# Abstract 64x96 single-port SRAM (pin interface of OpenROAD-flow-scripts' bsg_fakeram).
# Geometry is an assumption for a 16A-class node, not PDK data.
VERSION 5.8 ;
BUSBITCHARS "[]" ;
DIVIDERCHAR "/" ;

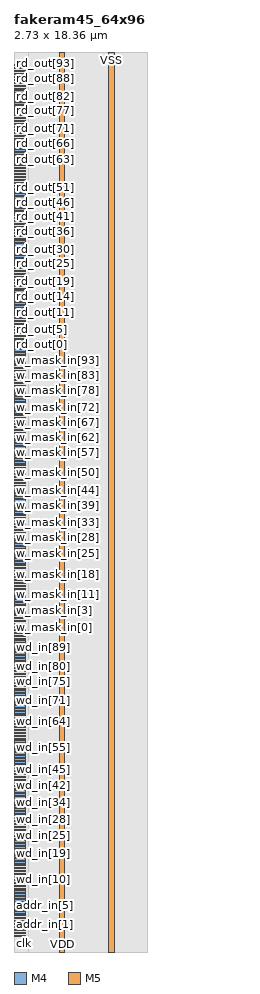
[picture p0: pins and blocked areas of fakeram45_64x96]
MACRO fakeram45_64x96
  CLASS BLOCK ;
  FOREIGN fakeram45_64x96 0 0 ;
  ORIGIN 0 0 ;
  SIZE 2.7300 BY 18.3600 ;
  SYMMETRY X Y R90 ;
  PIN clk
    DIRECTION INPUT ;
    USE CLOCK ;
    PORT
      LAYER M4 ;
        RECT 0 0.3150 0.2400 0.3450 ;
    END
  END clk
  PIN ce_in
    DIRECTION INPUT ;
    USE SIGNAL ;
    PORT
      LAYER M4 ;
        RECT 0 0.3750 0.2400 0.4050 ;
    END
  END ce_in
  PIN we_in
    DIRECTION INPUT ;
    USE SIGNAL ;
    PORT
      LAYER M4 ;
        RECT 0 0.4350 0.2400 0.4650 ;
    END
  END we_in
  PIN addr_in[0]
    DIRECTION INPUT ;
    USE SIGNAL ;
    PORT
      LAYER M4 ;
        RECT 0 0.4950 0.2400 0.5250 ;
    END
  END addr_in[0]
  PIN addr_in[1]
    DIRECTION INPUT ;
    USE SIGNAL ;
    PORT
      LAYER M4 ;
        RECT 0 0.5550 0.2400 0.5850 ;
    END
  END addr_in[1]
  PIN addr_in[2]
    DIRECTION INPUT ;
    USE SIGNAL ;
    PORT
      LAYER M4 ;
        RECT 0 0.6150 0.2400 0.6450 ;
    END
  END addr_in[2]
  PIN addr_in[3]
    DIRECTION INPUT ;
    USE SIGNAL ;
    PORT
      LAYER M4 ;
        RECT 0 0.6750 0.2400 0.7050 ;
    END
  END addr_in[3]
  PIN addr_in[4]
    DIRECTION INPUT ;
    USE SIGNAL ;
    PORT
      LAYER M4 ;
        RECT 0 0.7350 0.2400 0.7650 ;
    END
  END addr_in[4]
  PIN addr_in[5]
    DIRECTION INPUT ;
    USE SIGNAL ;
    PORT
      LAYER M4 ;
        RECT 0 0.7950 0.2400 0.8250 ;
    END
  END addr_in[5]
  PIN wd_in[0]
    DIRECTION INPUT ;
    USE SIGNAL ;
    PORT
      LAYER M4 ;
        RECT 0 0.8550 0.2400 0.8850 ;
    END
  END wd_in[0]
  PIN wd_in[1]
    DIRECTION INPUT ;
    USE SIGNAL ;
    PORT
      LAYER M4 ;
        RECT 0 0.9150 0.2400 0.9450 ;
    END
  END wd_in[1]
  PIN wd_in[2]
    DIRECTION INPUT ;
    USE SIGNAL ;
    PORT
      LAYER M4 ;
        RECT 0 0.9750 0.2400 1.0050 ;
    END
  END wd_in[2]
  PIN wd_in[3]
    DIRECTION INPUT ;
    USE SIGNAL ;
    PORT
      LAYER M4 ;
        RECT 0 1.0350 0.2400 1.0650 ;
    END
  END wd_in[3]
  PIN wd_in[4]
    DIRECTION INPUT ;
    USE SIGNAL ;
    PORT
      LAYER M4 ;
        RECT 0 1.0950 0.2400 1.1250 ;
    END
  END wd_in[4]
  PIN wd_in[5]
    DIRECTION INPUT ;
    USE SIGNAL ;
    PORT
      LAYER M4 ;
        RECT 0 1.1550 0.2400 1.1850 ;
    END
  END wd_in[5]
  PIN wd_in[6]
    DIRECTION INPUT ;
    USE SIGNAL ;
    PORT
      LAYER M4 ;
        RECT 0 1.2150 0.2400 1.2450 ;
    END
  END wd_in[6]
  PIN wd_in[7]
    DIRECTION INPUT ;
    USE SIGNAL ;
    PORT
      LAYER M4 ;
        RECT 0 1.2750 0.2400 1.3050 ;
    END
  END wd_in[7]
  PIN wd_in[8]
    DIRECTION INPUT ;
    USE SIGNAL ;
    PORT
      LAYER M4 ;
        RECT 0 1.3350 0.2400 1.3650 ;
    END
  END wd_in[8]
  PIN wd_in[9]
    DIRECTION INPUT ;
    USE SIGNAL ;
    PORT
      LAYER M4 ;
        RECT 0 1.3950 0.2400 1.4250 ;
    END
  END wd_in[9]
  PIN wd_in[10]
    DIRECTION INPUT ;
    USE SIGNAL ;
    PORT
      LAYER M4 ;
        RECT 0 1.4550 0.2400 1.4850 ;
    END
  END wd_in[10]
  PIN wd_in[11]
    DIRECTION INPUT ;
    USE SIGNAL ;
    PORT
      LAYER M4 ;
        RECT 0 1.5150 0.2400 1.5450 ;
    END
  END wd_in[11]
  PIN wd_in[12]
    DIRECTION INPUT ;
    USE SIGNAL ;
    PORT
      LAYER M4 ;
        RECT 0 1.5750 0.2400 1.6050 ;
    END
  END wd_in[12]
  PIN wd_in[13]
    DIRECTION INPUT ;
    USE SIGNAL ;
    PORT
      LAYER M4 ;
        RECT 0 1.6350 0.2400 1.6650 ;
    END
  END wd_in[13]
  PIN wd_in[14]
    DIRECTION INPUT ;
    USE SIGNAL ;
    PORT
      LAYER M4 ;
        RECT 0 1.6950 0.2400 1.7250 ;
    END
  END wd_in[14]
  PIN wd_in[15]
    DIRECTION INPUT ;
    USE SIGNAL ;
    PORT
      LAYER M4 ;
        RECT 0 1.7550 0.2400 1.7850 ;
    END
  END wd_in[15]
  PIN wd_in[16]
    DIRECTION INPUT ;
    USE SIGNAL ;
    PORT
      LAYER M4 ;
        RECT 0 1.8150 0.2400 1.8450 ;
    END
  END wd_in[16]
  PIN wd_in[17]
    DIRECTION INPUT ;
    USE SIGNAL ;
    PORT
      LAYER M4 ;
        RECT 0 1.8750 0.2400 1.9050 ;
    END
  END wd_in[17]
  PIN wd_in[18]
    DIRECTION INPUT ;
    USE SIGNAL ;
    PORT
      LAYER M4 ;
        RECT 0 1.9350 0.2400 1.9650 ;
    END
  END wd_in[18]
  PIN wd_in[19]
    DIRECTION INPUT ;
    USE SIGNAL ;
    PORT
      LAYER M4 ;
        RECT 0 1.9950 0.2400 2.0250 ;
    END
  END wd_in[19]
  PIN wd_in[20]
    DIRECTION INPUT ;
    USE SIGNAL ;
    PORT
      LAYER M4 ;
        RECT 0 2.0550 0.2400 2.0850 ;
    END
  END wd_in[20]
  PIN wd_in[21]
    DIRECTION INPUT ;
    USE SIGNAL ;
    PORT
      LAYER M4 ;
        RECT 0 2.1150 0.2400 2.1450 ;
    END
  END wd_in[21]
  PIN wd_in[22]
    DIRECTION INPUT ;
    USE SIGNAL ;
    PORT
      LAYER M4 ;
        RECT 0 2.1750 0.2400 2.2050 ;
    END
  END wd_in[22]
  PIN wd_in[23]
    DIRECTION INPUT ;
    USE SIGNAL ;
    PORT
      LAYER M4 ;
        RECT 0 2.2350 0.2400 2.2650 ;
    END
  END wd_in[23]
  PIN wd_in[24]
    DIRECTION INPUT ;
    USE SIGNAL ;
    PORT
      LAYER M4 ;
        RECT 0 2.2950 0.2400 2.3250 ;
    END
  END wd_in[24]
  PIN wd_in[25]
    DIRECTION INPUT ;
    USE SIGNAL ;
    PORT
      LAYER M4 ;
        RECT 0 2.3550 0.2400 2.3850 ;
    END
  END wd_in[25]
  PIN wd_in[26]
    DIRECTION INPUT ;
    USE SIGNAL ;
    PORT
      LAYER M4 ;
        RECT 0 2.4150 0.2400 2.4450 ;
    END
  END wd_in[26]
  PIN wd_in[27]
    DIRECTION INPUT ;
    USE SIGNAL ;
    PORT
      LAYER M4 ;
        RECT 0 2.4750 0.2400 2.5050 ;
    END
  END wd_in[27]
  PIN wd_in[28]
    DIRECTION INPUT ;
    USE SIGNAL ;
    PORT
      LAYER M4 ;
        RECT 0 2.5350 0.2400 2.5650 ;
    END
  END wd_in[28]
  PIN wd_in[29]
    DIRECTION INPUT ;
    USE SIGNAL ;
    PORT
      LAYER M4 ;
        RECT 0 2.5950 0.2400 2.6250 ;
    END
  END wd_in[29]
  PIN wd_in[30]
    DIRECTION INPUT ;
    USE SIGNAL ;
    PORT
      LAYER M4 ;
        RECT 0 2.6550 0.2400 2.6850 ;
    END
  END wd_in[30]
  PIN wd_in[31]
    DIRECTION INPUT ;
    USE SIGNAL ;
    PORT
      LAYER M4 ;
        RECT 0 2.7150 0.2400 2.7450 ;
    END
  END wd_in[31]
  PIN wd_in[32]
    DIRECTION INPUT ;
    USE SIGNAL ;
    PORT
      LAYER M4 ;
        RECT 0 2.7750 0.2400 2.8050 ;
    END
  END wd_in[32]
  PIN wd_in[33]
    DIRECTION INPUT ;
    USE SIGNAL ;
    PORT
      LAYER M4 ;
        RECT 0 2.8350 0.2400 2.8650 ;
    END
  END wd_in[33]
  PIN wd_in[34]
    DIRECTION INPUT ;
    USE SIGNAL ;
    PORT
      LAYER M4 ;
        RECT 0 2.8950 0.2400 2.9250 ;
    END
  END wd_in[34]
  PIN wd_in[35]
    DIRECTION INPUT ;
    USE SIGNAL ;
    PORT
      LAYER M4 ;
        RECT 0 2.9550 0.2400 2.9850 ;
    END
  END wd_in[35]
  PIN wd_in[36]
    DIRECTION INPUT ;
    USE SIGNAL ;
    PORT
      LAYER M4 ;
        RECT 0 3.0150 0.2400 3.0450 ;
    END
  END wd_in[36]
  PIN wd_in[37]
    DIRECTION INPUT ;
    USE SIGNAL ;
    PORT
      LAYER M4 ;
        RECT 0 3.0750 0.2400 3.1050 ;
    END
  END wd_in[37]
  PIN wd_in[38]
    DIRECTION INPUT ;
    USE SIGNAL ;
    PORT
      LAYER M4 ;
        RECT 0 3.1350 0.2400 3.1650 ;
    END
  END wd_in[38]
  PIN wd_in[39]
    DIRECTION INPUT ;
    USE SIGNAL ;
    PORT
      LAYER M4 ;
        RECT 0 3.1950 0.2400 3.2250 ;
    END
  END wd_in[39]
  PIN wd_in[40]
    DIRECTION INPUT ;
    USE SIGNAL ;
    PORT
      LAYER M4 ;
        RECT 0 3.2550 0.2400 3.2850 ;
    END
  END wd_in[40]
  PIN wd_in[41]
    DIRECTION INPUT ;
    USE SIGNAL ;
    PORT
      LAYER M4 ;
        RECT 0 3.3150 0.2400 3.3450 ;
    END
  END wd_in[41]
  PIN wd_in[42]
    DIRECTION INPUT ;
    USE SIGNAL ;
    PORT
      LAYER M4 ;
        RECT 0 3.3750 0.2400 3.4050 ;
    END
  END wd_in[42]
  PIN wd_in[43]
    DIRECTION INPUT ;
    USE SIGNAL ;
    PORT
      LAYER M4 ;
        RECT 0 3.4350 0.2400 3.4650 ;
    END
  END wd_in[43]
  PIN wd_in[44]
    DIRECTION INPUT ;
    USE SIGNAL ;
    PORT
      LAYER M4 ;
        RECT 0 3.4950 0.2400 3.5250 ;
    END
  END wd_in[44]
  PIN wd_in[45]
    DIRECTION INPUT ;
    USE SIGNAL ;
    PORT
      LAYER M4 ;
        RECT 0 3.5550 0.2400 3.5850 ;
    END
  END wd_in[45]
  PIN wd_in[46]
    DIRECTION INPUT ;
    USE SIGNAL ;
    PORT
      LAYER M4 ;
        RECT 0 3.6150 0.2400 3.6450 ;
    END
  END wd_in[46]
  PIN wd_in[47]
    DIRECTION INPUT ;
    USE SIGNAL ;
    PORT
      LAYER M4 ;
        RECT 0 3.6750 0.2400 3.7050 ;
    END
  END wd_in[47]
  PIN wd_in[48]
    DIRECTION INPUT ;
    USE SIGNAL ;
    PORT
      LAYER M4 ;
        RECT 0 3.7350 0.2400 3.7650 ;
    END
  END wd_in[48]
  PIN wd_in[49]
    DIRECTION INPUT ;
    USE SIGNAL ;
    PORT
      LAYER M4 ;
        RECT 0 3.7950 0.2400 3.8250 ;
    END
  END wd_in[49]
  PIN wd_in[50]
    DIRECTION INPUT ;
    USE SIGNAL ;
    PORT
      LAYER M4 ;
        RECT 0 3.8550 0.2400 3.8850 ;
    END
  END wd_in[50]
  PIN wd_in[51]
    DIRECTION INPUT ;
    USE SIGNAL ;
    PORT
      LAYER M4 ;
        RECT 0 3.9150 0.2400 3.9450 ;
    END
  END wd_in[51]
  PIN wd_in[52]
    DIRECTION INPUT ;
    USE SIGNAL ;
    PORT
      LAYER M4 ;
        RECT 0 3.9750 0.2400 4.0050 ;
    END
  END wd_in[52]
  PIN wd_in[53]
    DIRECTION INPUT ;
    USE SIGNAL ;
    PORT
      LAYER M4 ;
        RECT 0 4.0350 0.2400 4.0650 ;
    END
  END wd_in[53]
  PIN wd_in[54]
    DIRECTION INPUT ;
    USE SIGNAL ;
    PORT
      LAYER M4 ;
        RECT 0 4.0950 0.2400 4.1250 ;
    END
  END wd_in[54]
  PIN wd_in[55]
    DIRECTION INPUT ;
    USE SIGNAL ;
    PORT
      LAYER M4 ;
        RECT 0 4.1550 0.2400 4.1850 ;
    END
  END wd_in[55]
  PIN wd_in[56]
    DIRECTION INPUT ;
    USE SIGNAL ;
    PORT
      LAYER M4 ;
        RECT 0 4.2150 0.2400 4.2450 ;
    END
  END wd_in[56]
  PIN wd_in[57]
    DIRECTION INPUT ;
    USE SIGNAL ;
    PORT
      LAYER M4 ;
        RECT 0 4.2750 0.2400 4.3050 ;
    END
  END wd_in[57]
  PIN wd_in[58]
    DIRECTION INPUT ;
    USE SIGNAL ;
    PORT
      LAYER M4 ;
        RECT 0 4.3350 0.2400 4.3650 ;
    END
  END wd_in[58]
  PIN wd_in[59]
    DIRECTION INPUT ;
    USE SIGNAL ;
    PORT
      LAYER M4 ;
        RECT 0 4.3950 0.2400 4.4250 ;
    END
  END wd_in[59]
  PIN wd_in[60]
    DIRECTION INPUT ;
    USE SIGNAL ;
    PORT
      LAYER M4 ;
        RECT 0 4.4550 0.2400 4.4850 ;
    END
  END wd_in[60]
  PIN wd_in[61]
    DIRECTION INPUT ;
    USE SIGNAL ;
    PORT
      LAYER M4 ;
        RECT 0 4.5150 0.2400 4.5450 ;
    END
  END wd_in[61]
  PIN wd_in[62]
    DIRECTION INPUT ;
    USE SIGNAL ;
    PORT
      LAYER M4 ;
        RECT 0 4.5750 0.2400 4.6050 ;
    END
  END wd_in[62]
  PIN wd_in[63]
    DIRECTION INPUT ;
    USE SIGNAL ;
    PORT
      LAYER M4 ;
        RECT 0 4.6350 0.2400 4.6650 ;
    END
  END wd_in[63]
  PIN wd_in[64]
    DIRECTION INPUT ;
    USE SIGNAL ;
    PORT
      LAYER M4 ;
        RECT 0 4.6950 0.2400 4.7250 ;
    END
  END wd_in[64]
  PIN wd_in[65]
    DIRECTION INPUT ;
    USE SIGNAL ;
    PORT
      LAYER M4 ;
        RECT 0 4.7550 0.2400 4.7850 ;
    END
  END wd_in[65]
  PIN wd_in[66]
    DIRECTION INPUT ;
    USE SIGNAL ;
    PORT
      LAYER M4 ;
        RECT 0 4.8150 0.2400 4.8450 ;
    END
  END wd_in[66]
  PIN wd_in[67]
    DIRECTION INPUT ;
    USE SIGNAL ;
    PORT
      LAYER M4 ;
        RECT 0 4.8750 0.2400 4.9050 ;
    END
  END wd_in[67]
  PIN wd_in[68]
    DIRECTION INPUT ;
    USE SIGNAL ;
    PORT
      LAYER M4 ;
        RECT 0 4.9350 0.2400 4.9650 ;
    END
  END wd_in[68]
  PIN wd_in[69]
    DIRECTION INPUT ;
    USE SIGNAL ;
    PORT
      LAYER M4 ;
        RECT 0 4.9950 0.2400 5.0250 ;
    END
  END wd_in[69]
  PIN wd_in[70]
    DIRECTION INPUT ;
    USE SIGNAL ;
    PORT
      LAYER M4 ;
        RECT 0 5.0550 0.2400 5.0850 ;
    END
  END wd_in[70]
  PIN wd_in[71]
    DIRECTION INPUT ;
    USE SIGNAL ;
    PORT
      LAYER M4 ;
        RECT 0 5.1150 0.2400 5.1450 ;
    END
  END wd_in[71]
  PIN wd_in[72]
    DIRECTION INPUT ;
    USE SIGNAL ;
    PORT
      LAYER M4 ;
        RECT 0 5.1750 0.2400 5.2050 ;
    END
  END wd_in[72]
  PIN wd_in[73]
    DIRECTION INPUT ;
    USE SIGNAL ;
    PORT
      LAYER M4 ;
        RECT 0 5.2350 0.2400 5.2650 ;
    END
  END wd_in[73]
  PIN wd_in[74]
    DIRECTION INPUT ;
    USE SIGNAL ;
    PORT
      LAYER M4 ;
        RECT 0 5.2950 0.2400 5.3250 ;
    END
  END wd_in[74]
  PIN wd_in[75]
    DIRECTION INPUT ;
    USE SIGNAL ;
    PORT
      LAYER M4 ;
        RECT 0 5.3550 0.2400 5.3850 ;
    END
  END wd_in[75]
  PIN wd_in[76]
    DIRECTION INPUT ;
    USE SIGNAL ;
    PORT
      LAYER M4 ;
        RECT 0 5.4150 0.2400 5.4450 ;
    END
  END wd_in[76]
  PIN wd_in[77]
    DIRECTION INPUT ;
    USE SIGNAL ;
    PORT
      LAYER M4 ;
        RECT 0 5.4750 0.2400 5.5050 ;
    END
  END wd_in[77]
  PIN wd_in[78]
    DIRECTION INPUT ;
    USE SIGNAL ;
    PORT
      LAYER M4 ;
        RECT 0 5.5350 0.2400 5.5650 ;
    END
  END wd_in[78]
  PIN wd_in[79]
    DIRECTION INPUT ;
    USE SIGNAL ;
    PORT
      LAYER M4 ;
        RECT 0 5.5950 0.2400 5.6250 ;
    END
  END wd_in[79]
  PIN wd_in[80]
    DIRECTION INPUT ;
    USE SIGNAL ;
    PORT
      LAYER M4 ;
        RECT 0 5.6550 0.2400 5.6850 ;
    END
  END wd_in[80]
  PIN wd_in[81]
    DIRECTION INPUT ;
    USE SIGNAL ;
    PORT
      LAYER M4 ;
        RECT 0 5.7150 0.2400 5.7450 ;
    END
  END wd_in[81]
  PIN wd_in[82]
    DIRECTION INPUT ;
    USE SIGNAL ;
    PORT
      LAYER M4 ;
        RECT 0 5.7750 0.2400 5.8050 ;
    END
  END wd_in[82]
  PIN wd_in[83]
    DIRECTION INPUT ;
    USE SIGNAL ;
    PORT
      LAYER M4 ;
        RECT 0 5.8350 0.2400 5.8650 ;
    END
  END wd_in[83]
  PIN wd_in[84]
    DIRECTION INPUT ;
    USE SIGNAL ;
    PORT
      LAYER M4 ;
        RECT 0 5.8950 0.2400 5.9250 ;
    END
  END wd_in[84]
  PIN wd_in[85]
    DIRECTION INPUT ;
    USE SIGNAL ;
    PORT
      LAYER M4 ;
        RECT 0 5.9550 0.2400 5.9850 ;
    END
  END wd_in[85]
  PIN wd_in[86]
    DIRECTION INPUT ;
    USE SIGNAL ;
    PORT
      LAYER M4 ;
        RECT 0 6.0150 0.2400 6.0450 ;
    END
  END wd_in[86]
  PIN wd_in[87]
    DIRECTION INPUT ;
    USE SIGNAL ;
    PORT
      LAYER M4 ;
        RECT 0 6.0750 0.2400 6.1050 ;
    END
  END wd_in[87]
  PIN wd_in[88]
    DIRECTION INPUT ;
    USE SIGNAL ;
    PORT
      LAYER M4 ;
        RECT 0 6.1350 0.2400 6.1650 ;
    END
  END wd_in[88]
  PIN wd_in[89]
    DIRECTION INPUT ;
    USE SIGNAL ;
    PORT
      LAYER M4 ;
        RECT 0 6.1950 0.2400 6.2250 ;
    END
  END wd_in[89]
  PIN wd_in[90]
    DIRECTION INPUT ;
    USE SIGNAL ;
    PORT
      LAYER M4 ;
        RECT 0 6.2550 0.2400 6.2850 ;
    END
  END wd_in[90]
  PIN wd_in[91]
    DIRECTION INPUT ;
    USE SIGNAL ;
    PORT
      LAYER M4 ;
        RECT 0 6.3150 0.2400 6.3450 ;
    END
  END wd_in[91]
  PIN wd_in[92]
    DIRECTION INPUT ;
    USE SIGNAL ;
    PORT
      LAYER M4 ;
        RECT 0 6.3750 0.2400 6.4050 ;
    END
  END wd_in[92]
  PIN wd_in[93]
    DIRECTION INPUT ;
    USE SIGNAL ;
    PORT
      LAYER M4 ;
        RECT 0 6.4350 0.2400 6.4650 ;
    END
  END wd_in[93]
  PIN wd_in[94]
    DIRECTION INPUT ;
    USE SIGNAL ;
    PORT
      LAYER M4 ;
        RECT 0 6.4950 0.2400 6.5250 ;
    END
  END wd_in[94]
  PIN wd_in[95]
    DIRECTION INPUT ;
    USE SIGNAL ;
    PORT
      LAYER M4 ;
        RECT 0 6.5550 0.2400 6.5850 ;
    END
  END wd_in[95]
  PIN w_mask_in[0]
    DIRECTION INPUT ;
    USE SIGNAL ;
    PORT
      LAYER M4 ;
        RECT 0 6.6150 0.2400 6.6450 ;
    END
  END w_mask_in[0]
  PIN w_mask_in[1]
    DIRECTION INPUT ;
    USE SIGNAL ;
    PORT
      LAYER M4 ;
        RECT 0 6.6750 0.2400 6.7050 ;
    END
  END w_mask_in[1]
  PIN w_mask_in[2]
    DIRECTION INPUT ;
    USE SIGNAL ;
    PORT
      LAYER M4 ;
        RECT 0 6.7350 0.2400 6.7650 ;
    END
  END w_mask_in[2]
  PIN w_mask_in[3]
    DIRECTION INPUT ;
    USE SIGNAL ;
    PORT
      LAYER M4 ;
        RECT 0 6.7950 0.2400 6.8250 ;
    END
  END w_mask_in[3]
  PIN w_mask_in[4]
    DIRECTION INPUT ;
    USE SIGNAL ;
    PORT
      LAYER M4 ;
        RECT 0 6.8550 0.2400 6.8850 ;
    END
  END w_mask_in[4]
  PIN w_mask_in[5]
    DIRECTION INPUT ;
    USE SIGNAL ;
    PORT
      LAYER M4 ;
        RECT 0 6.9150 0.2400 6.9450 ;
    END
  END w_mask_in[5]
  PIN w_mask_in[6]
    DIRECTION INPUT ;
    USE SIGNAL ;
    PORT
      LAYER M4 ;
        RECT 0 6.9750 0.2400 7.0050 ;
    END
  END w_mask_in[6]
  PIN w_mask_in[7]
    DIRECTION INPUT ;
    USE SIGNAL ;
    PORT
      LAYER M4 ;
        RECT 0 7.0350 0.2400 7.0650 ;
    END
  END w_mask_in[7]
  PIN w_mask_in[8]
    DIRECTION INPUT ;
    USE SIGNAL ;
    PORT
      LAYER M4 ;
        RECT 0 7.0950 0.2400 7.1250 ;
    END
  END w_mask_in[8]
  PIN w_mask_in[9]
    DIRECTION INPUT ;
    USE SIGNAL ;
    PORT
      LAYER M4 ;
        RECT 0 7.1550 0.2400 7.1850 ;
    END
  END w_mask_in[9]
  PIN w_mask_in[10]
    DIRECTION INPUT ;
    USE SIGNAL ;
    PORT
      LAYER M4 ;
        RECT 0 7.2150 0.2400 7.2450 ;
    END
  END w_mask_in[10]
  PIN w_mask_in[11]
    DIRECTION INPUT ;
    USE SIGNAL ;
    PORT
      LAYER M4 ;
        RECT 0 7.2750 0.2400 7.3050 ;
    END
  END w_mask_in[11]
  PIN w_mask_in[12]
    DIRECTION INPUT ;
    USE SIGNAL ;
    PORT
      LAYER M4 ;
        RECT 0 7.3350 0.2400 7.3650 ;
    END
  END w_mask_in[12]
  PIN w_mask_in[13]
    DIRECTION INPUT ;
    USE SIGNAL ;
    PORT
      LAYER M4 ;
        RECT 0 7.3950 0.2400 7.4250 ;
    END
  END w_mask_in[13]
  PIN w_mask_in[14]
    DIRECTION INPUT ;
    USE SIGNAL ;
    PORT
      LAYER M4 ;
        RECT 0 7.4550 0.2400 7.4850 ;
    END
  END w_mask_in[14]
  PIN w_mask_in[15]
    DIRECTION INPUT ;
    USE SIGNAL ;
    PORT
      LAYER M4 ;
        RECT 0 7.5150 0.2400 7.5450 ;
    END
  END w_mask_in[15]
  PIN w_mask_in[16]
    DIRECTION INPUT ;
    USE SIGNAL ;
    PORT
      LAYER M4 ;
        RECT 0 7.5750 0.2400 7.6050 ;
    END
  END w_mask_in[16]
  PIN w_mask_in[17]
    DIRECTION INPUT ;
    USE SIGNAL ;
    PORT
      LAYER M4 ;
        RECT 0 7.6350 0.2400 7.6650 ;
    END
  END w_mask_in[17]
  PIN w_mask_in[18]
    DIRECTION INPUT ;
    USE SIGNAL ;
    PORT
      LAYER M4 ;
        RECT 0 7.6950 0.2400 7.7250 ;
    END
  END w_mask_in[18]
  PIN w_mask_in[19]
    DIRECTION INPUT ;
    USE SIGNAL ;
    PORT
      LAYER M4 ;
        RECT 0 7.7550 0.2400 7.7850 ;
    END
  END w_mask_in[19]
  PIN w_mask_in[20]
    DIRECTION INPUT ;
    USE SIGNAL ;
    PORT
      LAYER M4 ;
        RECT 0 7.8150 0.2400 7.8450 ;
    END
  END w_mask_in[20]
  PIN w_mask_in[21]
    DIRECTION INPUT ;
    USE SIGNAL ;
    PORT
      LAYER M4 ;
        RECT 0 7.8750 0.2400 7.9050 ;
    END
  END w_mask_in[21]
  PIN w_mask_in[22]
    DIRECTION INPUT ;
    USE SIGNAL ;
    PORT
      LAYER M4 ;
        RECT 0 7.9350 0.2400 7.9650 ;
    END
  END w_mask_in[22]
  PIN w_mask_in[23]
    DIRECTION INPUT ;
    USE SIGNAL ;
    PORT
      LAYER M4 ;
        RECT 0 7.9950 0.2400 8.0250 ;
    END
  END w_mask_in[23]
  PIN w_mask_in[24]
    DIRECTION INPUT ;
    USE SIGNAL ;
    PORT
      LAYER M4 ;
        RECT 0 8.0550 0.2400 8.0850 ;
    END
  END w_mask_in[24]
  PIN w_mask_in[25]
    DIRECTION INPUT ;
    USE SIGNAL ;
    PORT
      LAYER M4 ;
        RECT 0 8.1150 0.2400 8.1450 ;
    END
  END w_mask_in[25]
  PIN w_mask_in[26]
    DIRECTION INPUT ;
    USE SIGNAL ;
    PORT
      LAYER M4 ;
        RECT 0 8.1750 0.2400 8.2050 ;
    END
  END w_mask_in[26]
  PIN w_mask_in[27]
    DIRECTION INPUT ;
    USE SIGNAL ;
    PORT
      LAYER M4 ;
        RECT 0 8.2350 0.2400 8.2650 ;
    END
  END w_mask_in[27]
  PIN w_mask_in[28]
    DIRECTION INPUT ;
    USE SIGNAL ;
    PORT
      LAYER M4 ;
        RECT 0 8.2950 0.2400 8.3250 ;
    END
  END w_mask_in[28]
  PIN w_mask_in[29]
    DIRECTION INPUT ;
    USE SIGNAL ;
    PORT
      LAYER M4 ;
        RECT 0 8.3550 0.2400 8.3850 ;
    END
  END w_mask_in[29]
  PIN w_mask_in[30]
    DIRECTION INPUT ;
    USE SIGNAL ;
    PORT
      LAYER M4 ;
        RECT 0 8.4150 0.2400 8.4450 ;
    END
  END w_mask_in[30]
  PIN w_mask_in[31]
    DIRECTION INPUT ;
    USE SIGNAL ;
    PORT
      LAYER M4 ;
        RECT 0 8.4750 0.2400 8.5050 ;
    END
  END w_mask_in[31]
  PIN w_mask_in[32]
    DIRECTION INPUT ;
    USE SIGNAL ;
    PORT
      LAYER M4 ;
        RECT 0 8.5350 0.2400 8.5650 ;
    END
  END w_mask_in[32]
  PIN w_mask_in[33]
    DIRECTION INPUT ;
    USE SIGNAL ;
    PORT
      LAYER M4 ;
        RECT 0 8.5950 0.2400 8.6250 ;
    END
  END w_mask_in[33]
  PIN w_mask_in[34]
    DIRECTION INPUT ;
    USE SIGNAL ;
    PORT
      LAYER M4 ;
        RECT 0 8.6550 0.2400 8.6850 ;
    END
  END w_mask_in[34]
  PIN w_mask_in[35]
    DIRECTION INPUT ;
    USE SIGNAL ;
    PORT
      LAYER M4 ;
        RECT 0 8.7150 0.2400 8.7450 ;
    END
  END w_mask_in[35]
  PIN w_mask_in[36]
    DIRECTION INPUT ;
    USE SIGNAL ;
    PORT
      LAYER M4 ;
        RECT 0 8.7750 0.2400 8.8050 ;
    END
  END w_mask_in[36]
  PIN w_mask_in[37]
    DIRECTION INPUT ;
    USE SIGNAL ;
    PORT
      LAYER M4 ;
        RECT 0 8.8350 0.2400 8.8650 ;
    END
  END w_mask_in[37]
  PIN w_mask_in[38]
    DIRECTION INPUT ;
    USE SIGNAL ;
    PORT
      LAYER M4 ;
        RECT 0 8.8950 0.2400 8.9250 ;
    END
  END w_mask_in[38]
  PIN w_mask_in[39]
    DIRECTION INPUT ;
    USE SIGNAL ;
    PORT
      LAYER M4 ;
        RECT 0 8.9550 0.2400 8.9850 ;
    END
  END w_mask_in[39]
  PIN w_mask_in[40]
    DIRECTION INPUT ;
    USE SIGNAL ;
    PORT
      LAYER M4 ;
        RECT 0 9.0150 0.2400 9.0450 ;
    END
  END w_mask_in[40]
  PIN w_mask_in[41]
    DIRECTION INPUT ;
    USE SIGNAL ;
    PORT
      LAYER M4 ;
        RECT 0 9.0750 0.2400 9.1050 ;
    END
  END w_mask_in[41]
  PIN w_mask_in[42]
    DIRECTION INPUT ;
    USE SIGNAL ;
    PORT
      LAYER M4 ;
        RECT 0 9.1350 0.2400 9.1650 ;
    END
  END w_mask_in[42]
  PIN w_mask_in[43]
    DIRECTION INPUT ;
    USE SIGNAL ;
    PORT
      LAYER M4 ;
        RECT 0 9.1950 0.2400 9.2250 ;
    END
  END w_mask_in[43]
  PIN w_mask_in[44]
    DIRECTION INPUT ;
    USE SIGNAL ;
    PORT
      LAYER M4 ;
        RECT 0 9.2550 0.2400 9.2850 ;
    END
  END w_mask_in[44]
  PIN w_mask_in[45]
    DIRECTION INPUT ;
    USE SIGNAL ;
    PORT
      LAYER M4 ;
        RECT 0 9.3150 0.2400 9.3450 ;
    END
  END w_mask_in[45]
  PIN w_mask_in[46]
    DIRECTION INPUT ;
    USE SIGNAL ;
    PORT
      LAYER M4 ;
        RECT 0 9.3750 0.2400 9.4050 ;
    END
  END w_mask_in[46]
  PIN w_mask_in[47]
    DIRECTION INPUT ;
    USE SIGNAL ;
    PORT
      LAYER M4 ;
        RECT 0 9.4350 0.2400 9.4650 ;
    END
  END w_mask_in[47]
  PIN w_mask_in[48]
    DIRECTION INPUT ;
    USE SIGNAL ;
    PORT
      LAYER M4 ;
        RECT 0 9.4950 0.2400 9.5250 ;
    END
  END w_mask_in[48]
  PIN w_mask_in[49]
    DIRECTION INPUT ;
    USE SIGNAL ;
    PORT
      LAYER M4 ;
        RECT 0 9.5550 0.2400 9.5850 ;
    END
  END w_mask_in[49]
  PIN w_mask_in[50]
    DIRECTION INPUT ;
    USE SIGNAL ;
    PORT
      LAYER M4 ;
        RECT 0 9.6150 0.2400 9.6450 ;
    END
  END w_mask_in[50]
  PIN w_mask_in[51]
    DIRECTION INPUT ;
    USE SIGNAL ;
    PORT
      LAYER M4 ;
        RECT 0 9.6750 0.2400 9.7050 ;
    END
  END w_mask_in[51]
  PIN w_mask_in[52]
    DIRECTION INPUT ;
    USE SIGNAL ;
    PORT
      LAYER M4 ;
        RECT 0 9.7350 0.2400 9.7650 ;
    END
  END w_mask_in[52]
  PIN w_mask_in[53]
    DIRECTION INPUT ;
    USE SIGNAL ;
    PORT
      LAYER M4 ;
        RECT 0 9.7950 0.2400 9.8250 ;
    END
  END w_mask_in[53]
  PIN w_mask_in[54]
    DIRECTION INPUT ;
    USE SIGNAL ;
    PORT
      LAYER M4 ;
        RECT 0 9.8550 0.2400 9.8850 ;
    END
  END w_mask_in[54]
  PIN w_mask_in[55]
    DIRECTION INPUT ;
    USE SIGNAL ;
    PORT
      LAYER M4 ;
        RECT 0 9.9150 0.2400 9.9450 ;
    END
  END w_mask_in[55]
  PIN w_mask_in[56]
    DIRECTION INPUT ;
    USE SIGNAL ;
    PORT
      LAYER M4 ;
        RECT 0 9.9750 0.2400 10.0050 ;
    END
  END w_mask_in[56]
  PIN w_mask_in[57]
    DIRECTION INPUT ;
    USE SIGNAL ;
    PORT
      LAYER M4 ;
        RECT 0 10.0350 0.2400 10.0650 ;
    END
  END w_mask_in[57]
  PIN w_mask_in[58]
    DIRECTION INPUT ;
    USE SIGNAL ;
    PORT
      LAYER M4 ;
        RECT 0 10.0950 0.2400 10.1250 ;
    END
  END w_mask_in[58]
  PIN w_mask_in[59]
    DIRECTION INPUT ;
    USE SIGNAL ;
    PORT
      LAYER M4 ;
        RECT 0 10.1550 0.2400 10.1850 ;
    END
  END w_mask_in[59]
  PIN w_mask_in[60]
    DIRECTION INPUT ;
    USE SIGNAL ;
    PORT
      LAYER M4 ;
        RECT 0 10.2150 0.2400 10.2450 ;
    END
  END w_mask_in[60]
  PIN w_mask_in[61]
    DIRECTION INPUT ;
    USE SIGNAL ;
    PORT
      LAYER M4 ;
        RECT 0 10.2750 0.2400 10.3050 ;
    END
  END w_mask_in[61]
  PIN w_mask_in[62]
    DIRECTION INPUT ;
    USE SIGNAL ;
    PORT
      LAYER M4 ;
        RECT 0 10.3350 0.2400 10.3650 ;
    END
  END w_mask_in[62]
  PIN w_mask_in[63]
    DIRECTION INPUT ;
    USE SIGNAL ;
    PORT
      LAYER M4 ;
        RECT 0 10.3950 0.2400 10.4250 ;
    END
  END w_mask_in[63]
  PIN w_mask_in[64]
    DIRECTION INPUT ;
    USE SIGNAL ;
    PORT
      LAYER M4 ;
        RECT 0 10.4550 0.2400 10.4850 ;
    END
  END w_mask_in[64]
  PIN w_mask_in[65]
    DIRECTION INPUT ;
    USE SIGNAL ;
    PORT
      LAYER M4 ;
        RECT 0 10.5150 0.2400 10.5450 ;
    END
  END w_mask_in[65]
  PIN w_mask_in[66]
    DIRECTION INPUT ;
    USE SIGNAL ;
    PORT
      LAYER M4 ;
        RECT 0 10.5750 0.2400 10.6050 ;
    END
  END w_mask_in[66]
  PIN w_mask_in[67]
    DIRECTION INPUT ;
    USE SIGNAL ;
    PORT
      LAYER M4 ;
        RECT 0 10.6350 0.2400 10.6650 ;
    END
  END w_mask_in[67]
  PIN w_mask_in[68]
    DIRECTION INPUT ;
    USE SIGNAL ;
    PORT
      LAYER M4 ;
        RECT 0 10.6950 0.2400 10.7250 ;
    END
  END w_mask_in[68]
  PIN w_mask_in[69]
    DIRECTION INPUT ;
    USE SIGNAL ;
    PORT
      LAYER M4 ;
        RECT 0 10.7550 0.2400 10.7850 ;
    END
  END w_mask_in[69]
  PIN w_mask_in[70]
    DIRECTION INPUT ;
    USE SIGNAL ;
    PORT
      LAYER M4 ;
        RECT 0 10.8150 0.2400 10.8450 ;
    END
  END w_mask_in[70]
  PIN w_mask_in[71]
    DIRECTION INPUT ;
    USE SIGNAL ;
    PORT
      LAYER M4 ;
        RECT 0 10.8750 0.2400 10.9050 ;
    END
  END w_mask_in[71]
  PIN w_mask_in[72]
    DIRECTION INPUT ;
    USE SIGNAL ;
    PORT
      LAYER M4 ;
        RECT 0 10.9350 0.2400 10.9650 ;
    END
  END w_mask_in[72]
  PIN w_mask_in[73]
    DIRECTION INPUT ;
    USE SIGNAL ;
    PORT
      LAYER M4 ;
        RECT 0 10.9950 0.2400 11.0250 ;
    END
  END w_mask_in[73]
  PIN w_mask_in[74]
    DIRECTION INPUT ;
    USE SIGNAL ;
    PORT
      LAYER M4 ;
        RECT 0 11.0550 0.2400 11.0850 ;
    END
  END w_mask_in[74]
  PIN w_mask_in[75]
    DIRECTION INPUT ;
    USE SIGNAL ;
    PORT
      LAYER M4 ;
        RECT 0 11.1150 0.2400 11.1450 ;
    END
  END w_mask_in[75]
  PIN w_mask_in[76]
    DIRECTION INPUT ;
    USE SIGNAL ;
    PORT
      LAYER M4 ;
        RECT 0 11.1750 0.2400 11.2050 ;
    END
  END w_mask_in[76]
  PIN w_mask_in[77]
    DIRECTION INPUT ;
    USE SIGNAL ;
    PORT
      LAYER M4 ;
        RECT 0 11.2350 0.2400 11.2650 ;
    END
  END w_mask_in[77]
  PIN w_mask_in[78]
    DIRECTION INPUT ;
    USE SIGNAL ;
    PORT
      LAYER M4 ;
        RECT 0 11.2950 0.2400 11.3250 ;
    END
  END w_mask_in[78]
  PIN w_mask_in[79]
    DIRECTION INPUT ;
    USE SIGNAL ;
    PORT
      LAYER M4 ;
        RECT 0 11.3550 0.2400 11.3850 ;
    END
  END w_mask_in[79]
  PIN w_mask_in[80]
    DIRECTION INPUT ;
    USE SIGNAL ;
    PORT
      LAYER M4 ;
        RECT 0 11.4150 0.2400 11.4450 ;
    END
  END w_mask_in[80]
  PIN w_mask_in[81]
    DIRECTION INPUT ;
    USE SIGNAL ;
    PORT
      LAYER M4 ;
        RECT 0 11.4750 0.2400 11.5050 ;
    END
  END w_mask_in[81]
  PIN w_mask_in[82]
    DIRECTION INPUT ;
    USE SIGNAL ;
    PORT
      LAYER M4 ;
        RECT 0 11.5350 0.2400 11.5650 ;
    END
  END w_mask_in[82]
  PIN w_mask_in[83]
    DIRECTION INPUT ;
    USE SIGNAL ;
    PORT
      LAYER M4 ;
        RECT 0 11.5950 0.2400 11.6250 ;
    END
  END w_mask_in[83]
  PIN w_mask_in[84]
    DIRECTION INPUT ;
    USE SIGNAL ;
    PORT
      LAYER M4 ;
        RECT 0 11.6550 0.2400 11.6850 ;
    END
  END w_mask_in[84]
  PIN w_mask_in[85]
    DIRECTION INPUT ;
    USE SIGNAL ;
    PORT
      LAYER M4 ;
        RECT 0 11.7150 0.2400 11.7450 ;
    END
  END w_mask_in[85]
  PIN w_mask_in[86]
    DIRECTION INPUT ;
    USE SIGNAL ;
    PORT
      LAYER M4 ;
        RECT 0 11.7750 0.2400 11.8050 ;
    END
  END w_mask_in[86]
  PIN w_mask_in[87]
    DIRECTION INPUT ;
    USE SIGNAL ;
    PORT
      LAYER M4 ;
        RECT 0 11.8350 0.2400 11.8650 ;
    END
  END w_mask_in[87]
  PIN w_mask_in[88]
    DIRECTION INPUT ;
    USE SIGNAL ;
    PORT
      LAYER M4 ;
        RECT 0 11.8950 0.2400 11.9250 ;
    END
  END w_mask_in[88]
  PIN w_mask_in[89]
    DIRECTION INPUT ;
    USE SIGNAL ;
    PORT
      LAYER M4 ;
        RECT 0 11.9550 0.2400 11.9850 ;
    END
  END w_mask_in[89]
  PIN w_mask_in[90]
    DIRECTION INPUT ;
    USE SIGNAL ;
    PORT
      LAYER M4 ;
        RECT 0 12.0150 0.2400 12.0450 ;
    END
  END w_mask_in[90]
  PIN w_mask_in[91]
    DIRECTION INPUT ;
    USE SIGNAL ;
    PORT
      LAYER M4 ;
        RECT 0 12.0750 0.2400 12.1050 ;
    END
  END w_mask_in[91]
  PIN w_mask_in[92]
    DIRECTION INPUT ;
    USE SIGNAL ;
    PORT
      LAYER M4 ;
        RECT 0 12.1350 0.2400 12.1650 ;
    END
  END w_mask_in[92]
  PIN w_mask_in[93]
    DIRECTION INPUT ;
    USE SIGNAL ;
    PORT
      LAYER M4 ;
        RECT 0 12.1950 0.2400 12.2250 ;
    END
  END w_mask_in[93]
  PIN w_mask_in[94]
    DIRECTION INPUT ;
    USE SIGNAL ;
    PORT
      LAYER M4 ;
        RECT 0 12.2550 0.2400 12.2850 ;
    END
  END w_mask_in[94]
  PIN w_mask_in[95]
    DIRECTION INPUT ;
    USE SIGNAL ;
    PORT
      LAYER M4 ;
        RECT 0 12.3150 0.2400 12.3450 ;
    END
  END w_mask_in[95]
  PIN rd_out[0]
    DIRECTION OUTPUT ;
    USE SIGNAL ;
    PORT
      LAYER M4 ;
        RECT 0 12.3750 0.2400 12.4050 ;
    END
  END rd_out[0]
  PIN rd_out[1]
    DIRECTION OUTPUT ;
    USE SIGNAL ;
    PORT
      LAYER M4 ;
        RECT 0 12.4350 0.2400 12.4650 ;
    END
  END rd_out[1]
  PIN rd_out[2]
    DIRECTION OUTPUT ;
    USE SIGNAL ;
    PORT
      LAYER M4 ;
        RECT 0 12.4950 0.2400 12.5250 ;
    END
  END rd_out[2]
  PIN rd_out[3]
    DIRECTION OUTPUT ;
    USE SIGNAL ;
    PORT
      LAYER M4 ;
        RECT 0 12.5550 0.2400 12.5850 ;
    END
  END rd_out[3]
  PIN rd_out[4]
    DIRECTION OUTPUT ;
    USE SIGNAL ;
    PORT
      LAYER M4 ;
        RECT 0 12.6150 0.2400 12.6450 ;
    END
  END rd_out[4]
  PIN rd_out[5]
    DIRECTION OUTPUT ;
    USE SIGNAL ;
    PORT
      LAYER M4 ;
        RECT 0 12.6750 0.2400 12.7050 ;
    END
  END rd_out[5]
  PIN rd_out[6]
    DIRECTION OUTPUT ;
    USE SIGNAL ;
    PORT
      LAYER M4 ;
        RECT 0 12.7350 0.2400 12.7650 ;
    END
  END rd_out[6]
  PIN rd_out[7]
    DIRECTION OUTPUT ;
    USE SIGNAL ;
    PORT
      LAYER M4 ;
        RECT 0 12.7950 0.2400 12.8250 ;
    END
  END rd_out[7]
  PIN rd_out[8]
    DIRECTION OUTPUT ;
    USE SIGNAL ;
    PORT
      LAYER M4 ;
        RECT 0 12.8550 0.2400 12.8850 ;
    END
  END rd_out[8]
  PIN rd_out[9]
    DIRECTION OUTPUT ;
    USE SIGNAL ;
    PORT
      LAYER M4 ;
        RECT 0 12.9150 0.2400 12.9450 ;
    END
  END rd_out[9]
  PIN rd_out[10]
    DIRECTION OUTPUT ;
    USE SIGNAL ;
    PORT
      LAYER M4 ;
        RECT 0 12.9750 0.2400 13.0050 ;
    END
  END rd_out[10]
  PIN rd_out[11]
    DIRECTION OUTPUT ;
    USE SIGNAL ;
    PORT
      LAYER M4 ;
        RECT 0 13.0350 0.2400 13.0650 ;
    END
  END rd_out[11]
  PIN rd_out[12]
    DIRECTION OUTPUT ;
    USE SIGNAL ;
    PORT
      LAYER M4 ;
        RECT 0 13.0950 0.2400 13.1250 ;
    END
  END rd_out[12]
  PIN rd_out[13]
    DIRECTION OUTPUT ;
    USE SIGNAL ;
    PORT
      LAYER M4 ;
        RECT 0 13.1550 0.2400 13.1850 ;
    END
  END rd_out[13]
  PIN rd_out[14]
    DIRECTION OUTPUT ;
    USE SIGNAL ;
    PORT
      LAYER M4 ;
        RECT 0 13.2150 0.2400 13.2450 ;
    END
  END rd_out[14]
  PIN rd_out[15]
    DIRECTION OUTPUT ;
    USE SIGNAL ;
    PORT
      LAYER M4 ;
        RECT 0 13.2750 0.2400 13.3050 ;
    END
  END rd_out[15]
  PIN rd_out[16]
    DIRECTION OUTPUT ;
    USE SIGNAL ;
    PORT
      LAYER M4 ;
        RECT 0 13.3350 0.2400 13.3650 ;
    END
  END rd_out[16]
  PIN rd_out[17]
    DIRECTION OUTPUT ;
    USE SIGNAL ;
    PORT
      LAYER M4 ;
        RECT 0 13.3950 0.2400 13.4250 ;
    END
  END rd_out[17]
  PIN rd_out[18]
    DIRECTION OUTPUT ;
    USE SIGNAL ;
    PORT
      LAYER M4 ;
        RECT 0 13.4550 0.2400 13.4850 ;
    END
  END rd_out[18]
  PIN rd_out[19]
    DIRECTION OUTPUT ;
    USE SIGNAL ;
    PORT
      LAYER M4 ;
        RECT 0 13.5150 0.2400 13.5450 ;
    END
  END rd_out[19]
  PIN rd_out[20]
    DIRECTION OUTPUT ;
    USE SIGNAL ;
    PORT
      LAYER M4 ;
        RECT 0 13.5750 0.2400 13.6050 ;
    END
  END rd_out[20]
  PIN rd_out[21]
    DIRECTION OUTPUT ;
    USE SIGNAL ;
    PORT
      LAYER M4 ;
        RECT 0 13.6350 0.2400 13.6650 ;
    END
  END rd_out[21]
  PIN rd_out[22]
    DIRECTION OUTPUT ;
    USE SIGNAL ;
    PORT
      LAYER M4 ;
        RECT 0 13.6950 0.2400 13.7250 ;
    END
  END rd_out[22]
  PIN rd_out[23]
    DIRECTION OUTPUT ;
    USE SIGNAL ;
    PORT
      LAYER M4 ;
        RECT 0 13.7550 0.2400 13.7850 ;
    END
  END rd_out[23]
  PIN rd_out[24]
    DIRECTION OUTPUT ;
    USE SIGNAL ;
    PORT
      LAYER M4 ;
        RECT 0 13.8150 0.2400 13.8450 ;
    END
  END rd_out[24]
  PIN rd_out[25]
    DIRECTION OUTPUT ;
    USE SIGNAL ;
    PORT
      LAYER M4 ;
        RECT 0 13.8750 0.2400 13.9050 ;
    END
  END rd_out[25]
  PIN rd_out[26]
    DIRECTION OUTPUT ;
    USE SIGNAL ;
    PORT
      LAYER M4 ;
        RECT 0 13.9350 0.2400 13.9650 ;
    END
  END rd_out[26]
  PIN rd_out[27]
    DIRECTION OUTPUT ;
    USE SIGNAL ;
    PORT
      LAYER M4 ;
        RECT 0 13.9950 0.2400 14.0250 ;
    END
  END rd_out[27]
  PIN rd_out[28]
    DIRECTION OUTPUT ;
    USE SIGNAL ;
    PORT
      LAYER M4 ;
        RECT 0 14.0550 0.2400 14.0850 ;
    END
  END rd_out[28]
  PIN rd_out[29]
    DIRECTION OUTPUT ;
    USE SIGNAL ;
    PORT
      LAYER M4 ;
        RECT 0 14.1150 0.2400 14.1450 ;
    END
  END rd_out[29]
  PIN rd_out[30]
    DIRECTION OUTPUT ;
    USE SIGNAL ;
    PORT
      LAYER M4 ;
        RECT 0 14.1750 0.2400 14.2050 ;
    END
  END rd_out[30]
  PIN rd_out[31]
    DIRECTION OUTPUT ;
    USE SIGNAL ;
    PORT
      LAYER M4 ;
        RECT 0 14.2350 0.2400 14.2650 ;
    END
  END rd_out[31]
  PIN rd_out[32]
    DIRECTION OUTPUT ;
    USE SIGNAL ;
    PORT
      LAYER M4 ;
        RECT 0 14.2950 0.2400 14.3250 ;
    END
  END rd_out[32]
  PIN rd_out[33]
    DIRECTION OUTPUT ;
    USE SIGNAL ;
    PORT
      LAYER M4 ;
        RECT 0 14.3550 0.2400 14.3850 ;
    END
  END rd_out[33]
  PIN rd_out[34]
    DIRECTION OUTPUT ;
    USE SIGNAL ;
    PORT
      LAYER M4 ;
        RECT 0 14.4150 0.2400 14.4450 ;
    END
  END rd_out[34]
  PIN rd_out[35]
    DIRECTION OUTPUT ;
    USE SIGNAL ;
    PORT
      LAYER M4 ;
        RECT 0 14.4750 0.2400 14.5050 ;
    END
  END rd_out[35]
  PIN rd_out[36]
    DIRECTION OUTPUT ;
    USE SIGNAL ;
    PORT
      LAYER M4 ;
        RECT 0 14.5350 0.2400 14.5650 ;
    END
  END rd_out[36]
  PIN rd_out[37]
    DIRECTION OUTPUT ;
    USE SIGNAL ;
    PORT
      LAYER M4 ;
        RECT 0 14.5950 0.2400 14.6250 ;
    END
  END rd_out[37]
  PIN rd_out[38]
    DIRECTION OUTPUT ;
    USE SIGNAL ;
    PORT
      LAYER M4 ;
        RECT 0 14.6550 0.2400 14.6850 ;
    END
  END rd_out[38]
  PIN rd_out[39]
    DIRECTION OUTPUT ;
    USE SIGNAL ;
    PORT
      LAYER M4 ;
        RECT 0 14.7150 0.2400 14.7450 ;
    END
  END rd_out[39]
  PIN rd_out[40]
    DIRECTION OUTPUT ;
    USE SIGNAL ;
    PORT
      LAYER M4 ;
        RECT 0 14.7750 0.2400 14.8050 ;
    END
  END rd_out[40]
  PIN rd_out[41]
    DIRECTION OUTPUT ;
    USE SIGNAL ;
    PORT
      LAYER M4 ;
        RECT 0 14.8350 0.2400 14.8650 ;
    END
  END rd_out[41]
  PIN rd_out[42]
    DIRECTION OUTPUT ;
    USE SIGNAL ;
    PORT
      LAYER M4 ;
        RECT 0 14.8950 0.2400 14.9250 ;
    END
  END rd_out[42]
  PIN rd_out[43]
    DIRECTION OUTPUT ;
    USE SIGNAL ;
    PORT
      LAYER M4 ;
        RECT 0 14.9550 0.2400 14.9850 ;
    END
  END rd_out[43]
  PIN rd_out[44]
    DIRECTION OUTPUT ;
    USE SIGNAL ;
    PORT
      LAYER M4 ;
        RECT 0 15.0150 0.2400 15.0450 ;
    END
  END rd_out[44]
  PIN rd_out[45]
    DIRECTION OUTPUT ;
    USE SIGNAL ;
    PORT
      LAYER M4 ;
        RECT 0 15.0750 0.2400 15.1050 ;
    END
  END rd_out[45]
  PIN rd_out[46]
    DIRECTION OUTPUT ;
    USE SIGNAL ;
    PORT
      LAYER M4 ;
        RECT 0 15.1350 0.2400 15.1650 ;
    END
  END rd_out[46]
  PIN rd_out[47]
    DIRECTION OUTPUT ;
    USE SIGNAL ;
    PORT
      LAYER M4 ;
        RECT 0 15.1950 0.2400 15.2250 ;
    END
  END rd_out[47]
  PIN rd_out[48]
    DIRECTION OUTPUT ;
    USE SIGNAL ;
    PORT
      LAYER M4 ;
        RECT 0 15.2550 0.2400 15.2850 ;
    END
  END rd_out[48]
  PIN rd_out[49]
    DIRECTION OUTPUT ;
    USE SIGNAL ;
    PORT
      LAYER M4 ;
        RECT 0 15.3150 0.2400 15.3450 ;
    END
  END rd_out[49]
  PIN rd_out[50]
    DIRECTION OUTPUT ;
    USE SIGNAL ;
    PORT
      LAYER M4 ;
        RECT 0 15.3750 0.2400 15.4050 ;
    END
  END rd_out[50]
  PIN rd_out[51]
    DIRECTION OUTPUT ;
    USE SIGNAL ;
    PORT
      LAYER M4 ;
        RECT 0 15.4350 0.2400 15.4650 ;
    END
  END rd_out[51]
  PIN rd_out[52]
    DIRECTION OUTPUT ;
    USE SIGNAL ;
    PORT
      LAYER M4 ;
        RECT 0 15.4950 0.2400 15.5250 ;
    END
  END rd_out[52]
  PIN rd_out[53]
    DIRECTION OUTPUT ;
    USE SIGNAL ;
    PORT
      LAYER M4 ;
        RECT 0 15.5550 0.2400 15.5850 ;
    END
  END rd_out[53]
  PIN rd_out[54]
    DIRECTION OUTPUT ;
    USE SIGNAL ;
    PORT
      LAYER M4 ;
        RECT 0 15.6150 0.2400 15.6450 ;
    END
  END rd_out[54]
  PIN rd_out[55]
    DIRECTION OUTPUT ;
    USE SIGNAL ;
    PORT
      LAYER M4 ;
        RECT 0 15.6750 0.2400 15.7050 ;
    END
  END rd_out[55]
  PIN rd_out[56]
    DIRECTION OUTPUT ;
    USE SIGNAL ;
    PORT
      LAYER M4 ;
        RECT 0 15.7350 0.2400 15.7650 ;
    END
  END rd_out[56]
  PIN rd_out[57]
    DIRECTION OUTPUT ;
    USE SIGNAL ;
    PORT
      LAYER M4 ;
        RECT 0 15.7950 0.2400 15.8250 ;
    END
  END rd_out[57]
  PIN rd_out[58]
    DIRECTION OUTPUT ;
    USE SIGNAL ;
    PORT
      LAYER M4 ;
        RECT 0 15.8550 0.2400 15.8850 ;
    END
  END rd_out[58]
  PIN rd_out[59]
    DIRECTION OUTPUT ;
    USE SIGNAL ;
    PORT
      LAYER M4 ;
        RECT 0 15.9150 0.2400 15.9450 ;
    END
  END rd_out[59]
  PIN rd_out[60]
    DIRECTION OUTPUT ;
    USE SIGNAL ;
    PORT
      LAYER M4 ;
        RECT 0 15.9750 0.2400 16.0050 ;
    END
  END rd_out[60]
  PIN rd_out[61]
    DIRECTION OUTPUT ;
    USE SIGNAL ;
    PORT
      LAYER M4 ;
        RECT 0 16.0350 0.2400 16.0650 ;
    END
  END rd_out[61]
  PIN rd_out[62]
    DIRECTION OUTPUT ;
    USE SIGNAL ;
    PORT
      LAYER M4 ;
        RECT 0 16.0950 0.2400 16.1250 ;
    END
  END rd_out[62]
  PIN rd_out[63]
    DIRECTION OUTPUT ;
    USE SIGNAL ;
    PORT
      LAYER M4 ;
        RECT 0 16.1550 0.2400 16.1850 ;
    END
  END rd_out[63]
  PIN rd_out[64]
    DIRECTION OUTPUT ;
    USE SIGNAL ;
    PORT
      LAYER M4 ;
        RECT 0 16.2150 0.2400 16.2450 ;
    END
  END rd_out[64]
  PIN rd_out[65]
    DIRECTION OUTPUT ;
    USE SIGNAL ;
    PORT
      LAYER M4 ;
        RECT 0 16.2750 0.2400 16.3050 ;
    END
  END rd_out[65]
  PIN rd_out[66]
    DIRECTION OUTPUT ;
    USE SIGNAL ;
    PORT
      LAYER M4 ;
        RECT 0 16.3350 0.2400 16.3650 ;
    END
  END rd_out[66]
  PIN rd_out[67]
    DIRECTION OUTPUT ;
    USE SIGNAL ;
    PORT
      LAYER M4 ;
        RECT 0 16.3950 0.2400 16.4250 ;
    END
  END rd_out[67]
  PIN rd_out[68]
    DIRECTION OUTPUT ;
    USE SIGNAL ;
    PORT
      LAYER M4 ;
        RECT 0 16.4550 0.2400 16.4850 ;
    END
  END rd_out[68]
  PIN rd_out[69]
    DIRECTION OUTPUT ;
    USE SIGNAL ;
    PORT
      LAYER M4 ;
        RECT 0 16.5150 0.2400 16.5450 ;
    END
  END rd_out[69]
  PIN rd_out[70]
    DIRECTION OUTPUT ;
    USE SIGNAL ;
    PORT
      LAYER M4 ;
        RECT 0 16.5750 0.2400 16.6050 ;
    END
  END rd_out[70]
  PIN rd_out[71]
    DIRECTION OUTPUT ;
    USE SIGNAL ;
    PORT
      LAYER M4 ;
        RECT 0 16.6350 0.2400 16.6650 ;
    END
  END rd_out[71]
  PIN rd_out[72]
    DIRECTION OUTPUT ;
    USE SIGNAL ;
    PORT
      LAYER M4 ;
        RECT 0 16.6950 0.2400 16.7250 ;
    END
  END rd_out[72]
  PIN rd_out[73]
    DIRECTION OUTPUT ;
    USE SIGNAL ;
    PORT
      LAYER M4 ;
        RECT 0 16.7550 0.2400 16.7850 ;
    END
  END rd_out[73]
  PIN rd_out[74]
    DIRECTION OUTPUT ;
    USE SIGNAL ;
    PORT
      LAYER M4 ;
        RECT 0 16.8150 0.2400 16.8450 ;
    END
  END rd_out[74]
  PIN rd_out[75]
    DIRECTION OUTPUT ;
    USE SIGNAL ;
    PORT
      LAYER M4 ;
        RECT 0 16.8750 0.2400 16.9050 ;
    END
  END rd_out[75]
  PIN rd_out[76]
    DIRECTION OUTPUT ;
    USE SIGNAL ;
    PORT
      LAYER M4 ;
        RECT 0 16.9350 0.2400 16.9650 ;
    END
  END rd_out[76]
  PIN rd_out[77]
    DIRECTION OUTPUT ;
    USE SIGNAL ;
    PORT
      LAYER M4 ;
        RECT 0 16.9950 0.2400 17.0250 ;
    END
  END rd_out[77]
  PIN rd_out[78]
    DIRECTION OUTPUT ;
    USE SIGNAL ;
    PORT
      LAYER M4 ;
        RECT 0 17.0550 0.2400 17.0850 ;
    END
  END rd_out[78]
  PIN rd_out[79]
    DIRECTION OUTPUT ;
    USE SIGNAL ;
    PORT
      LAYER M4 ;
        RECT 0 17.1150 0.2400 17.1450 ;
    END
  END rd_out[79]
  PIN rd_out[80]
    DIRECTION OUTPUT ;
    USE SIGNAL ;
    PORT
      LAYER M4 ;
        RECT 0 17.1750 0.2400 17.2050 ;
    END
  END rd_out[80]
  PIN rd_out[81]
    DIRECTION OUTPUT ;
    USE SIGNAL ;
    PORT
      LAYER M4 ;
        RECT 0 17.2350 0.2400 17.2650 ;
    END
  END rd_out[81]
  PIN rd_out[82]
    DIRECTION OUTPUT ;
    USE SIGNAL ;
    PORT
      LAYER M4 ;
        RECT 0 17.2950 0.2400 17.3250 ;
    END
  END rd_out[82]
  PIN rd_out[83]
    DIRECTION OUTPUT ;
    USE SIGNAL ;
    PORT
      LAYER M4 ;
        RECT 0 17.3550 0.2400 17.3850 ;
    END
  END rd_out[83]
  PIN rd_out[84]
    DIRECTION OUTPUT ;
    USE SIGNAL ;
    PORT
      LAYER M4 ;
        RECT 0 17.4150 0.2400 17.4450 ;
    END
  END rd_out[84]
  PIN rd_out[85]
    DIRECTION OUTPUT ;
    USE SIGNAL ;
    PORT
      LAYER M4 ;
        RECT 0 17.4750 0.2400 17.5050 ;
    END
  END rd_out[85]
  PIN rd_out[86]
    DIRECTION OUTPUT ;
    USE SIGNAL ;
    PORT
      LAYER M4 ;
        RECT 0 17.5350 0.2400 17.5650 ;
    END
  END rd_out[86]
  PIN rd_out[87]
    DIRECTION OUTPUT ;
    USE SIGNAL ;
    PORT
      LAYER M4 ;
        RECT 0 17.5950 0.2400 17.6250 ;
    END
  END rd_out[87]
  PIN rd_out[88]
    DIRECTION OUTPUT ;
    USE SIGNAL ;
    PORT
      LAYER M4 ;
        RECT 0 17.6550 0.2400 17.6850 ;
    END
  END rd_out[88]
  PIN rd_out[89]
    DIRECTION OUTPUT ;
    USE SIGNAL ;
    PORT
      LAYER M4 ;
        RECT 0 17.7150 0.2400 17.7450 ;
    END
  END rd_out[89]
  PIN rd_out[90]
    DIRECTION OUTPUT ;
    USE SIGNAL ;
    PORT
      LAYER M4 ;
        RECT 0 17.7750 0.2400 17.8050 ;
    END
  END rd_out[90]
  PIN rd_out[91]
    DIRECTION OUTPUT ;
    USE SIGNAL ;
    PORT
      LAYER M4 ;
        RECT 0 17.8350 0.2400 17.8650 ;
    END
  END rd_out[91]
  PIN rd_out[92]
    DIRECTION OUTPUT ;
    USE SIGNAL ;
    PORT
      LAYER M4 ;
        RECT 0 17.8950 0.2400 17.9250 ;
    END
  END rd_out[92]
  PIN rd_out[93]
    DIRECTION OUTPUT ;
    USE SIGNAL ;
    PORT
      LAYER M4 ;
        RECT 0 17.9550 0.2400 17.9850 ;
    END
  END rd_out[93]
  PIN rd_out[94]
    DIRECTION OUTPUT ;
    USE SIGNAL ;
    PORT
      LAYER M4 ;
        RECT 0 18.0150 0.2400 18.0450 ;
    END
  END rd_out[94]
  PIN rd_out[95]
    DIRECTION OUTPUT ;
    USE SIGNAL ;
    PORT
      LAYER M4 ;
        RECT 0 18.0750 0.2400 18.1050 ;
    END
  END rd_out[95]
  PIN VDD
    DIRECTION INOUT ;
    USE POWER ;
    PORT
      LAYER M5 ;
        RECT 0.9200 0 1.0400 18.3600 ;
    END
  END VDD
  PIN VSS
    DIRECTION INOUT ;
    USE GROUND ;
    PORT
      LAYER M5 ;
        RECT 1.9200 0 2.0400 18.3600 ;
    END
  END VSS
  OBS
    LAYER BPR ;
      RECT 0 0 2.7300 18.3600 ;
    LAYER M0 ;
      RECT 0 0 2.7300 18.3600 ;
    LAYER M1 ;
      RECT 0 0 2.7300 18.3600 ;
    LAYER M2 ;
      RECT 0 0 2.7300 18.3600 ;
    LAYER M3 ;
      RECT 0 0 2.7300 18.3600 ;
    LAYER BPR2TOP ;
      RECT 0 0 2.7300 18.3600 ;
    LAYER VIA0 ;
      RECT 0 0 2.7300 18.3600 ;
    LAYER VIA1 ;
      RECT 0 0 2.7300 18.3600 ;
    LAYER VIA2 ;
      RECT 0 0 2.7300 18.3600 ;
    LAYER VIA3 ;
      RECT 0 0 2.7300 18.3600 ;
    LAYER M4 ;
      RECT 0.3000 0 2.7300 18.3600 ;
  END
END fakeram45_64x96

END LIBRARY
